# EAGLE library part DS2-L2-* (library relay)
RELAY NAiS bistable, 2 x switch, 4 A/250 V

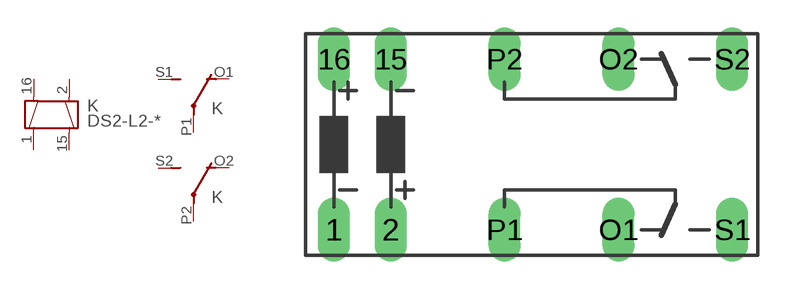
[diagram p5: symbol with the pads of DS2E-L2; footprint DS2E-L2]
Designator prefix K; gates 1=K2 2=U 3=U

## DS2-L2-1.5V (OC_FARNELL: unknown; OC_NEWARK: unknown), DS2-L2-12V (OC_FARNELL: unknown; OC_NEWARK: unknown), DS2-L2-24V (OC_FARNELL: unknown; OC_NEWARK: unknown), DS2-L2-3V (OC_FARNELL: unknown; OC_NEWARK: unknown), DS2-L2-48V (OC_FARNELL: unknown; OC_NEWARK: unknown), DS2-L2-5V (OC_FARNELL: unknown; OC_NEWARK: unknown), DS2-L2-6V (OC_FARNELL: unknown; OC_NEWARK: unknown), DS2-L2-9V (OC_FARNELL: unknown; OC_NEWARK: unknown)  [DS2E-L2]
1  1:2  pas
2  1:3  pas
15  1:4  pas
16  1:1  pas
O1  2:O  pas
O2  3:O  pas
P1  2:P  pas
P2  3:P  pas
S1  2:S  pas
S2  3:S  pas

## Footprint DS2E-L2 (pad centres in mm)
RELAY 2 x switch, 4 A/250 V, NAiS
drill 0.914 long: 1 -7.62,-3.81; 2 -5.08,-3.81; 15 -5.08,3.81; 16 -7.62,3.81; O1 5.08,-3.81; O2 5.08,3.81; P1 0,-3.81; P2 0,3.81; S1 10.16,-3.81; S2 10.16,3.81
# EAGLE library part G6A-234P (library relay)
RELAY 2 x switch, 0.3 A/125 V AC, 1 A/30 V DC, Omron

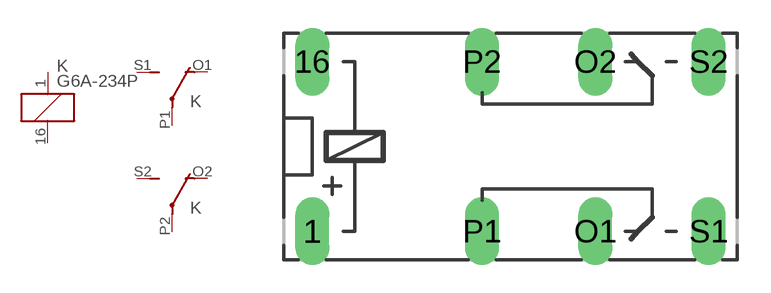
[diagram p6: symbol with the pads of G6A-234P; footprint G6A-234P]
Designator prefix K; gates 1=K 2=U 3=U

## G6A-234P (OC_FARNELL: unknown; OC_NEWARK: unknown)  [G6A-234P]
1  1:1  pas
16  1:2  pas
O1  2:O  pas
O2  3:O  pas
P1  2:P  pas
P2  3:P  pas
S1  2:S  pas
S2  3:S  pas

## Footprint G6A-234P (pad centres in mm)
RELAY 2 x switch, 0.3 A/125 V AC, 1 A/30 V DC, Omron
drill 1.016 long: 1 -3.81,-3.81; 16 -3.81,3.81; O1 8.89,-3.81; O2 8.89,3.81; P1 3.81,-3.81; P2 3.81,3.81; S1 13.97,-3.81; S2 13.97,3.81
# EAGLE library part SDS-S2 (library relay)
RELAY monostable, 2 x norm. open, 2 x norm. closed, 5 A/250 V AC/DC, NAiS

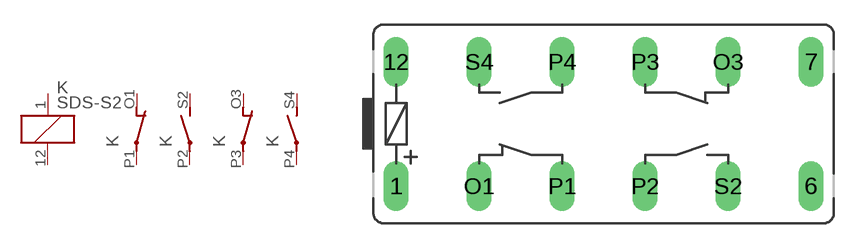
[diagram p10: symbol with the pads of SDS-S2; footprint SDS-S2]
Designator prefix K; gates 1=K 5=S 3=S 2=O 4=O

## SDS-S2 (OC_FARNELL: unknown; OC_NEWARK: unknown)  [SDS-S2]
1  1:1  pas
12  1:2  pas
O1  2:O  pas
O3  4:O  pas
P1  2:P  pas
P2  3:P  pas
P3  4:P  pas
P4  5:P  pas
S2  3:S  pas
S4  5:S  pas

## Footprint SDS-S2 (pad centres in mm)
RELAY mono stable, 2 x norm. open, 2 x norm. closed, 5 A/250 V, AC/DC, NAiS
drill 1.016 long: 1 -12.7,-3.81; 6 12.7,-3.81; 7 12.7,3.81; 12 -12.7,3.81; O1 -7.62,-3.81; O3 7.62,3.81; P1 -2.54,-3.81; P2 2.54,-3.81; P3 2.54,3.81; P4 -2.54,3.81; S2 7.62,-3.81; S4 -7.62,3.81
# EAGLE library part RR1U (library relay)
RELAY reed, polarity, 1 x switch with shield

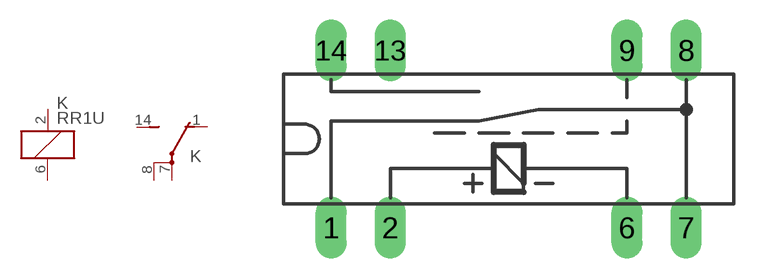
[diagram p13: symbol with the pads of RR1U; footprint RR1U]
Designator prefix K; gates 1=K 2=U1

## RR1U (OC_FARNELL: unknown; OC_NEWARK: unknown)  [RR1U]
1  2:O  pas
2  1:1  pas
6  1:2  pas
7  2:P  pas
8  2:P  pas
14  2:S  pas

## Footprint RR1U (pad centres in mm)
RELAY reed, polarity, 1 x switch with shield
drill 0.813 long: 1 -7.62,-3.81; 2 -5.08,-3.81; 6 5.08,-3.81; 7 7.62,-3.81; 8 7.62,3.81; 9 5.08,3.81; 13 -5.08,3.81; 14 -7.62,3.81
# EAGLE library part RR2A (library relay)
RELAY reed, polarity, 2 x norm. open

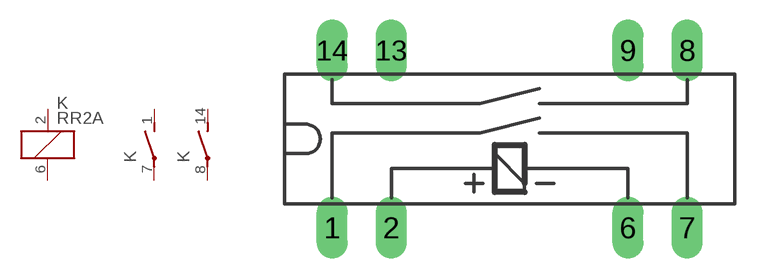
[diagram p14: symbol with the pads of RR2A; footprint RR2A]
Designator prefix K; gates 1=K 2=S 3=S

## RR2A (OC_FARNELL: unknown; OC_NEWARK: unknown)  [RR2A]
1  2:S  pas
2  1:1  pas
6  1:2  pas
7  2:P  pas
8  3:P  pas
14  3:S  pas

## Footprint RR2A (pad centres in mm)
RELAY reed, polarity, 2 x norm. open
drill 0.813 long: 1 -7.62,-3.81; 2 -5.08,-3.81; 6 5.08,-3.81; 7 7.62,-3.81; 8 7.62,3.81; 9 5.08,3.81; 13 -5.08,3.81; 14 -7.62,3.81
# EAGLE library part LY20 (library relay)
RELAY 2 x switch, Omron

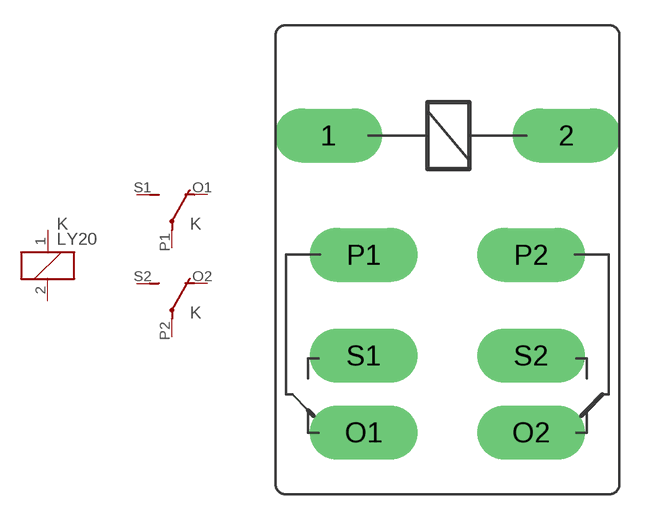
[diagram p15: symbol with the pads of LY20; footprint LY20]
Designator prefix K; gates 1=K 2=U 3=U

## LY20 (OC_FARNELL: unknown; OC_NEWARK: unknown)  [LY20]
1  1:1  pas
2  1:2  pas
O1  2:O  pas
O2  3:O  pas
P1  2:P  pas
P2  3:P  pas
S1  2:S  pas
S2  3:S  pas

## Footprint LY20 (pad centres in mm)
RELAY 2 x switch, Omron
drill 2.21 long: 1 -7.112,0; 2 7.112,0; O1 -5.004,-17.755; O2 5.004,-17.755; P1 -5.004,-7.137; P2 5.004,-7.137; S1 -5.004,-13.157; S2 5.004,-13.157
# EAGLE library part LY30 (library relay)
RELAY 3 x switch, Omron

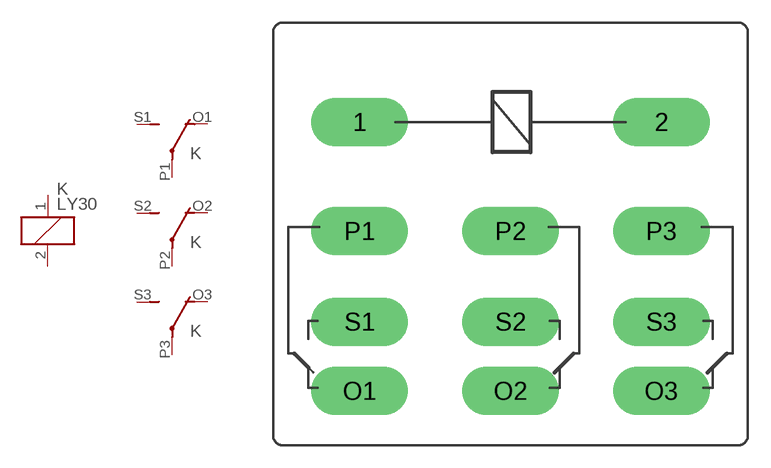
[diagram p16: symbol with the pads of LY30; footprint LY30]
Designator prefix K; gates 1=K 2=U 3=U 4=U

## LY30 (OC_FARNELL: unknown; OC_NEWARK: unknown)  [LY30]
1  1:1  pas
2  1:2  pas
O1  2:O  pas
O2  3:O  pas
O3  4:O  pas
P1  2:P  pas
P2  3:P  pas
P3  4:P  pas
S1  2:S  pas
S2  3:S  pas
S3  4:S  pas

## Footprint LY30 (pad centres in mm)
RELAY 3 x switch, Omron
drill 2.21 long: 1 -10.008,0; 2 10.008,0; O1 -10.008,-17.856; O2 0,-17.856; O3 10.008,-17.856; P1 -10.008,-7.239; P2 0,-7.239; P3 10.008,-7.239; S1 -10.008,-13.259; S2 0,-13.259; S3 10.008,-13.259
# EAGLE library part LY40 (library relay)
RELAY 4 x switch, Omron

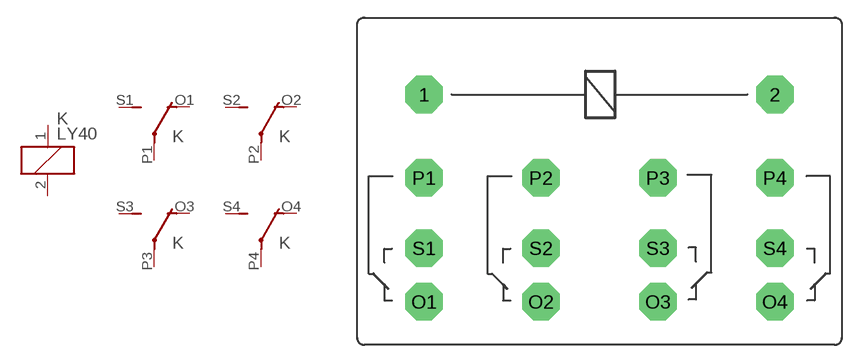
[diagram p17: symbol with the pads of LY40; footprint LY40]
Designator prefix K; gates 1=K 2=U 3=U 4=U 5=U

## LY40 (OC_FARNELL: unknown; OC_NEWARK: unknown)  [LY40]
1  1:1  pas
2  1:2  pas
O1  2:O  pas
O2  3:O  pas
O3  4:O  pas
O4  5:O  pas
P1  2:P  pas
P2  3:P  pas
P3  4:P  pas
P4  5:P  pas
S1  2:S  pas
S2  3:S  pas
S3  4:S  pas
S4  5:S  pas

## Footprint LY40 (pad centres in mm)
RELAY 4 x switch, Omron
drill 2.21 octagon: 1 -15.011,0; 2 15.011,0; O1 -15.011,-17.755; O2 -5.004,-17.755; O3 5.004,-17.755; O4 15.011,-17.755; P1 -15.011,-7.137; P2 -5.004,-7.137; P3 5.004,-7.137; P4 15.011,-7.137; S1 -15.011,-13.157; S2 -5.004,-13.157; S3 5.004,-13.157; S4 15.011,-13.157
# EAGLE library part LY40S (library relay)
RELAY 4 x switch, Omron

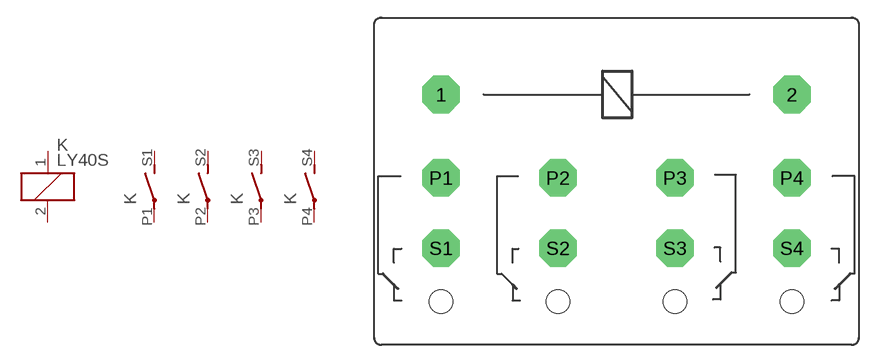
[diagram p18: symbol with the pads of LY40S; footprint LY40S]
Designator prefix K; gates 1=K 2=S 3=S 4=S 5=S

## LY40S (OC_FARNELL: unknown; OC_NEWARK: unknown)  [LY40S]
1  1:1  pas
2  1:2  pas
P1  2:P  pas
P2  3:P  pas
P3  4:P  pas
P4  5:P  pas
S1  2:S  pas
S2  3:S  pas
S3  4:S  pas
S4  5:S  pas

## Footprint LY40S (pad centres in mm)
RELAY 4 x switch, Omron
drill 2.21 octagon: 1 -15.011,0; 2 15.011,0; P1 -15.011,-7.137; P2 -5.004,-7.137; P3 5.004,-7.137; P4 15.011,-7.137; S1 -15.011,-13.157; S2 -5.004,-13.157; S3 5.004,-13.157; S4 15.011,-13.157
hole 2.007 at -15.011,-17.755
hole 2.007 at -5.004,-17.755
hole 2.007 at 5.004,-17.755
hole 2.007 at 15.011,-17.755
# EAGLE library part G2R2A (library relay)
RELAY 2 x norm. open, Omron

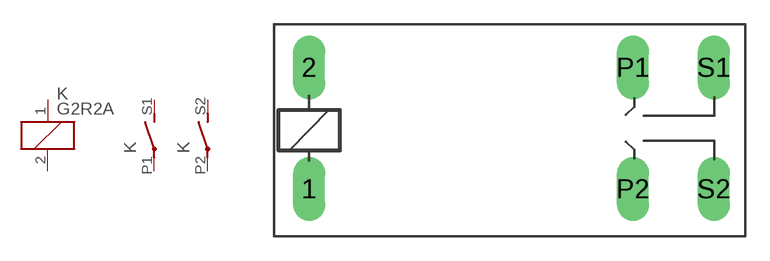
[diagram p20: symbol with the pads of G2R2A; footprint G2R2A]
Designator prefix K; gates 1=K 2=S 3=S

## G2R2A (MPN: G2R-2A-DC24; OC_FARNELL: 6985269; OC_NEWARK: 36M5257)  [G2R2A]
1  1:1  pas
2  1:2  pas
P1  2:P  pas
P2  3:P  pas
S1  2:S  pas
S2  3:S  pas

## Footprint G2R2A (pad centres in mm)
RELAY 2 x norm. open, Omron
drill 1.321 long: 1 -2.54,-3.683; 2 -2.54,3.81; P1 17.45,3.81; P2 17.45,-3.683; S1 22.454,3.81; S2 22.454,-3.683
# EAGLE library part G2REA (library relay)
RELAY 1 x norm. open, high current, Omron

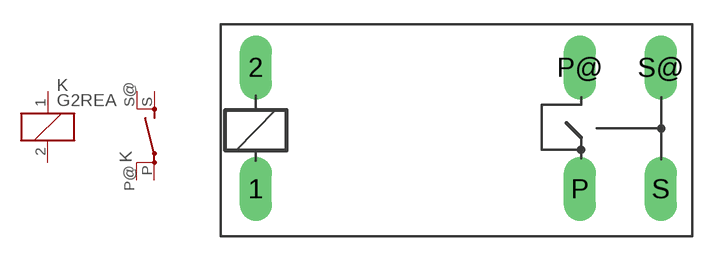
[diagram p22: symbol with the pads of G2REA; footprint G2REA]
Designator prefix K; gates 1=K 2=SD

## G2REA (OC_FARNELL: unknown; OC_NEWARK: unknown)  [G2REA]
1  1:1  pas
2  1:2  pas
P  2:P  pas
P@  2:P  pas
S  2:S  pas
S@  2:S  pas

## Footprint G2REA (pad centres in mm)
RELAY 1 x norm. open, high current, Omron
drill 1.321 long: 1 -2.54,-3.683; 2 -2.54,3.81; P 17.45,-3.683; P@ 17.45,3.81; S 22.454,-3.683; S@ 22.454,3.81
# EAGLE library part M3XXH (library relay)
RELAY 1 x switch

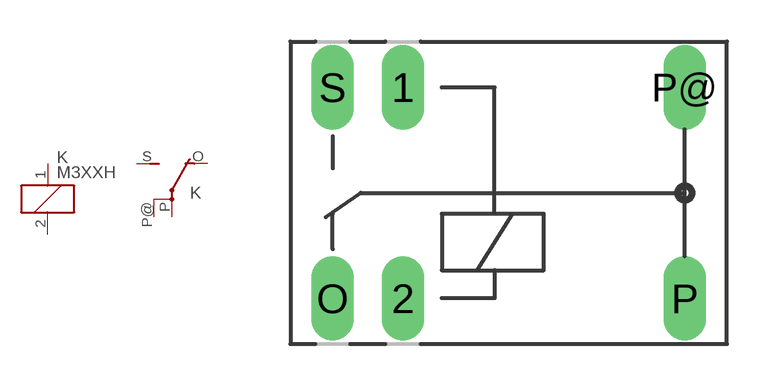
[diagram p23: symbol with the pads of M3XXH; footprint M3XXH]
Designator prefix K; gates 1=K 2=U1

## M3XXH (OC_FARNELL: unknown; OC_NEWARK: unknown)  [M3XXH]
1  1:1  pas
2  1:2  pas
O  2:O  pas
P  2:P  pas
P@  2:P  pas
S  2:S  pas

## Footprint M3XXH (pad centres in mm)
RELAY 1 x switch
drill 1.016 long: 1 -3.81,3.81; 2 -3.81,-3.81; O -6.35,-3.81; P 6.35,-3.81; P@ 6.35,3.81; S -6.35,3.81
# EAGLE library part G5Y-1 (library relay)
RELAY RF Relay up to 900 MHz, 1 x switch, 10 W, Omron

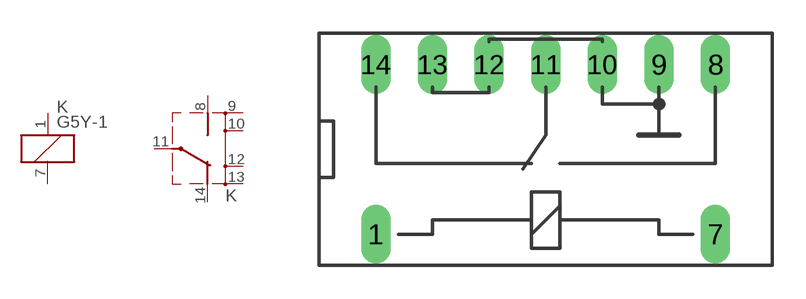
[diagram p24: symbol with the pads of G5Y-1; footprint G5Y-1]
Designator prefix K; gates 1=K 2=U_M4

## G5Y-1 (OC_FARNELL: unknown; OC_NEWARK: unknown)  [G5Y-1]
1  1:1  pas
7  1:2  pas
8  2:S  pas
9  2:ES  pas
10  2:ES  pas
11  2:P  pas
12  2:ES  pas
13  2:ES  pas
14  2:O  pas

## Footprint G5Y-1 (pad centres in mm)
RELAY RF up to 900 MHz, 1 x switch, 10 W, Omron
drill 0.813 long: 1 -7.62,-3.81; 7 7.62,-3.81; 8 7.62,3.81; 9 5.08,3.81; 10 2.54,3.81; 11 0,3.81; 12 -2.54,3.81; 13 -5.08,3.81; 14 -7.62,3.81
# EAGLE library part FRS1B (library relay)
RELAY 1 x switch, same as V23101-D6-A201, Siemens

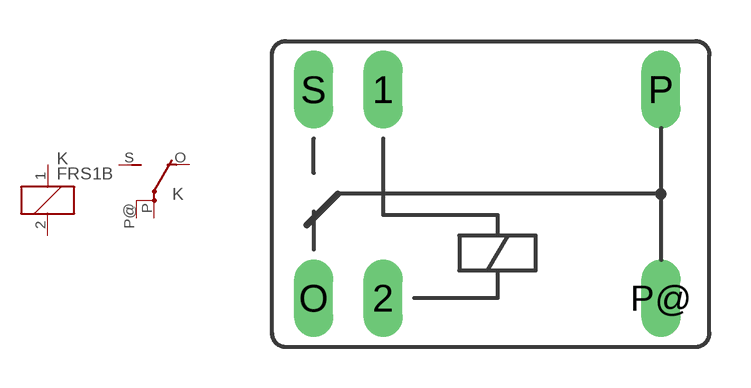
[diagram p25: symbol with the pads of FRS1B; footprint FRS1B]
Designator prefix K; gates 1=K 2=U1

## FRS1B (OC_FARNELL: unknown; OC_NEWARK: unknown)  [FRS1B]
1  1:1  pas
2  1:2  pas
O  2:O  pas
P  2:P  pas
P@  2:P  pas
S  2:S  pas

## Footprint FRS1B (pad centres in mm)
RELAY 1 x switch, same as V23101-D6-A201, Siemens
drill 0.914 long: 1 0,3.81; 2 0,-3.81; O -2.54,-3.81; P 10.16,3.81; P@ 10.16,-3.81; S -2.54,3.81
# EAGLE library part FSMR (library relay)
RELAY 1 x switch, same as FBR21D/H, Fujitsu

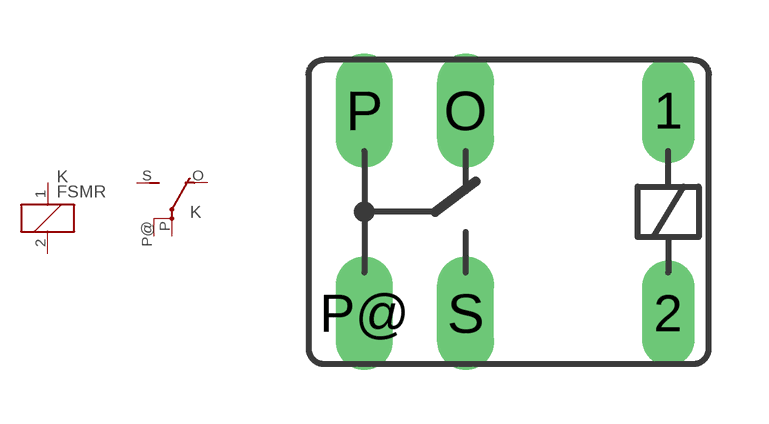
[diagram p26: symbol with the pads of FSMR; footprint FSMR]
Designator prefix K; gates 1=K 2=U1

## FSMR (OC_FARNELL: unknown; OC_NEWARK: unknown)  [FSMR]
1  1:1  pas
2  1:2  pas
O  2:O  pas
P  2:P  pas
P@  2:P  pas
S  2:S  pas

## Footprint FSMR (pad centres in mm)
RELAY 1 x switch, same as FBR21D/H, Fujitsu
drill 0.813 long: 1 5.08,2.54; 2 5.08,-2.54
drill 0.914 long: O 0,2.54; P -2.54,2.54; P@ -2.54,-2.54; S 0,-2.54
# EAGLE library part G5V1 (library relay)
RELAY 1 x switch, 0.5 A/125 V AC, 1 A/24 V DC , Omron

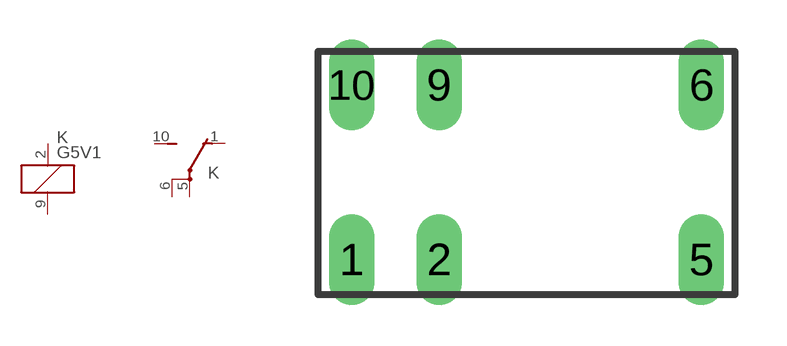
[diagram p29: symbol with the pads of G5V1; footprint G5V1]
Designator prefix K; gates 1=K 2=U1

## G5V1 (MPN: G5V-1-DC24; OC_FARNELL: 9949593; OC_NEWARK: 36M6377)  [G5V1]
1  2:O  pas
2  1:1  pas
5  2:P  pas
6  2:P  pas
9  1:2  pas
10  2:S  pas

## Footprint G5V1 (pad centres in mm)
RELAY 1 x switch, 0.5 A/125 V AC, 1 A/24 V DC , Omron
drill 0.813 long: 1 -5.08,-2.54; 2 -2.54,-2.54; 5 5.08,-2.54; 6 5.08,2.54; 9 -2.54,2.54; 10 -5.08,2.54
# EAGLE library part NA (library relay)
RELAY

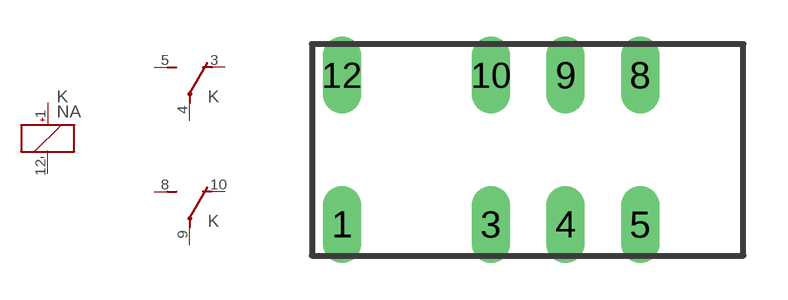
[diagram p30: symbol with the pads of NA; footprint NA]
Designator prefix K; gates 1=K+- 2=U 3=U

## NA (OC_FARNELL: unknown; OC_NEWARK: unknown)  [NA]
1  1:+  pas
3  2:O  pas
4  2:P  pas
5  2:S  pas
8  3:S  pas
9  3:P  pas
10  3:O  pas
12  1:-  pas

## Footprint NA (pad centres in mm)
RELAY dummy
drill 0.8 long: 1 -6.35,-2.54; 3 -1.27,-2.54; 4 1.27,-2.54; 5 3.81,-2.54; 8 3.81,2.54; 9 1.27,2.54; 10 -1.27,2.54; 12 -6.35,2.54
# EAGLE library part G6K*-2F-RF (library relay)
OMRON High Frequency Relay G6K-RF Compact High Frequency Relays with 2 Form C (DPDT) Contacts Handles 1 A, 30 VDC discrete load and 1 W at 1 GHz high frequency load D20G6KRF0602.pdf

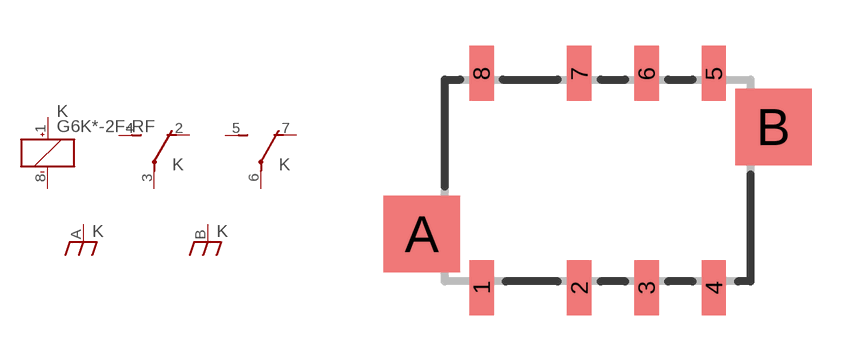
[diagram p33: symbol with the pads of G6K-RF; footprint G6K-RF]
Designator prefix K; gates 1=K+- A=U B=U S1=SHIELD S2=SHIELD

## G6K-2F-RF (MF: OMRON COMPONENTS USA; MPN: G6K-2F-RF-DC12; OC_FARNELL: 1448181; OC_NEWARK: 73C8948), G6KU-2F-RF (OC_FARNELL: unknown; OC_NEWARK: unknown)  [G6K-RF]
1  1:+  pas
2  A:O  pas
3  A:P  pas
4  A:S  pas
5  B:S  pas
6  B:P  pas
7  B:O  pas
8  1:-  pas
A  S1:SH  pas
B  S2:SH  pas

## Footprint G6K-RF (pad centres in mm)
OMRON High Frequency Relay G6K-RF D20G6KRF0602.pdf
smd 0.8 x 1.8: 1 -3.8,-3.5; 2 -0.6,-3.5; 3 1.6,-3.5; 4 3.8,-3.5; 5 3.8,3.5; 6 1.6,3.5; 7 -0.6,3.5; 8 -3.8,3.5
smd 2.5 x 2.5: A -5.75,-1.75; B 5.75,1.75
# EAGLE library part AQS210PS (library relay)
PhotoMOS Relay NAiS Source: http://www.mew-europe.com/.. pti_en.pdf

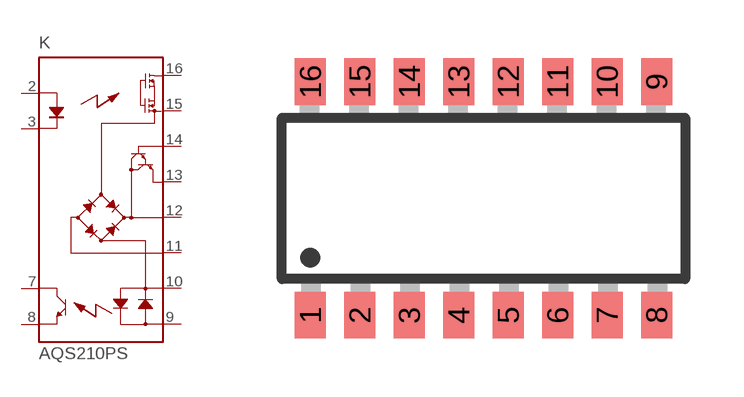
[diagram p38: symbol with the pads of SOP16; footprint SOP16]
Designator prefix K

## AQS210PS (OC_FARNELL: unknown; OC_NEWARK: unknown)  [SOP16]
2  2  pas
3  3  pas
7  7  pas
8  8  pas
9  9  pas
10  10  pas
11  11  pas
12  12  pas
13  13  pas
14  14  pas
15  15  pas
16  16  pas

## Footprint SOP16 (pad centres in mm)
SOP 16 - AQS21, AQS22, AQS610TS Series NAiS Source: http://www.mew-europe.com/.. pti_en.pdf
smd 0.8 x 1.2: 1 -4.445,-3; 2 -3.175,-3; 3 -1.905,-3; 4 -0.635,-3; 5 0.635,-3; 6 1.905,-3; 7 3.175,-3; 8 4.445,-3; 9 4.445,3; 10 3.175,3; 11 1.905,3; 12 0.635,3; 13 -0.635,3; 14 -1.905,3; 15 -3.175,3; 16 -4.445,3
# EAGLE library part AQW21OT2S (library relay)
PhotoMOS Relay NAiS Source: http://www.mew-europe.com/.. pti_en.pdf

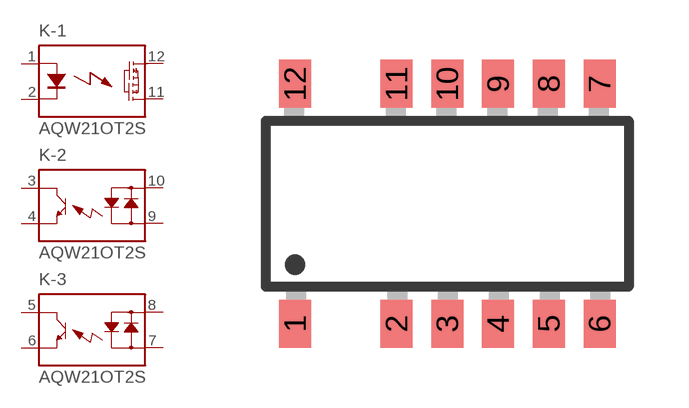
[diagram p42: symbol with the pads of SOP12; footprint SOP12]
Designator prefix K; gates -1=PHOTOMOS_2D -2=PHOTO-DETECTOR -3=PHOTO-DETECTOR

## AQW21OT2S (OC_FARNELL: unknown; OC_NEWARK: unknown)  [SOP12]
1  -1:A  pas
2  -1:K  pas
3  -2:K  pas
4  -2:E  pas
5  -3:K  pas
6  -3:E  pas
7  -3:AC2  pas
8  -3:AC1  pas
9  -2:AC2  pas
10  -2:AC1  pas
11  -1:DS2  pas
12  -1:DS1  pas

## Footprint SOP12 (pad centres in mm)
AOP 12- AQW21.T2s Series NAiS Source: http://www.mew-europe.com/.. pti_en.pdf
smd 0.8 x 1.2: 1 -3.81,-3; 2 -1.27,-3; 3 0,-3; 4 1.27,-3; 5 2.54,-3; 6 3.81,-3; 7 3.81,3; 8 2.54,3; 9 1.27,3; 10 0,3; 11 -1.27,3; 12 -3.81,3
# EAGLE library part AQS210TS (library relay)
PhotoMOS Relay NAiS Source: http://www.mew-europe.com/.. pti_en.pdf

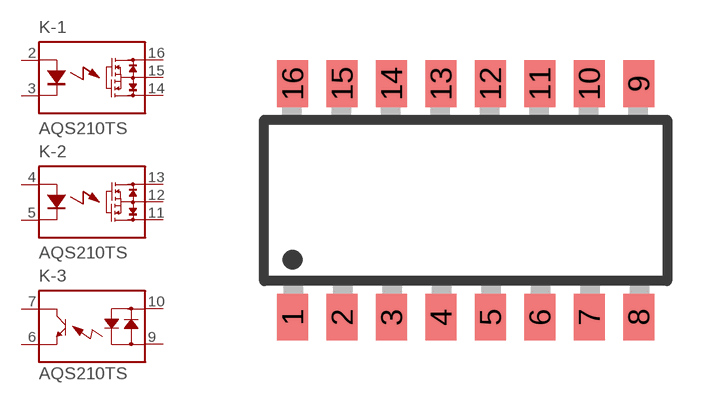
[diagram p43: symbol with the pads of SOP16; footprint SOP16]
Designator prefix K; gates -1=PHOTO-REKAY2D1S -2=PHOTO-REKAY2D1S -3=PHOTO-DETECTOR

## AQS210TS (OC_FARNELL: unknown; OC_NEWARK: unknown)  [SOP16]
2  -1:A  pas
3  -1:K  pas
4  -2:A  pas
5  -2:K  pas
6  -3:E  pas
7  -3:K  pas
9  -3:AC2  pas
10  -3:AC1  pas
11  -2:D2  pas
12  -2:S  pas
13  -2:D1  pas
14  -1:D2  pas
15  -1:S  pas
16  -1:D1  pas

## Footprint SOP16 (pad centres in mm)
SOP 16 - AQS21, AQS22, AQS610TS Series NAiS Source: http://www.mew-europe.com/.. pti_en.pdf
smd 0.8 x 1.2: 1 -4.445,-3; 2 -3.175,-3; 3 -1.905,-3; 4 -0.635,-3; 5 0.635,-3; 6 1.905,-3; 7 3.175,-3; 8 4.445,-3; 9 4.445,3; 10 3.175,3; 11 1.905,3; 12 0.635,3; 13 -0.635,3; 14 -1.905,3; 15 -3.175,3; 16 -4.445,3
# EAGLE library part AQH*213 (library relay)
SOLID STATE RELAY NAiS Source: http://www.mew-europe.com/.. en_ds_61613_0000.pdf

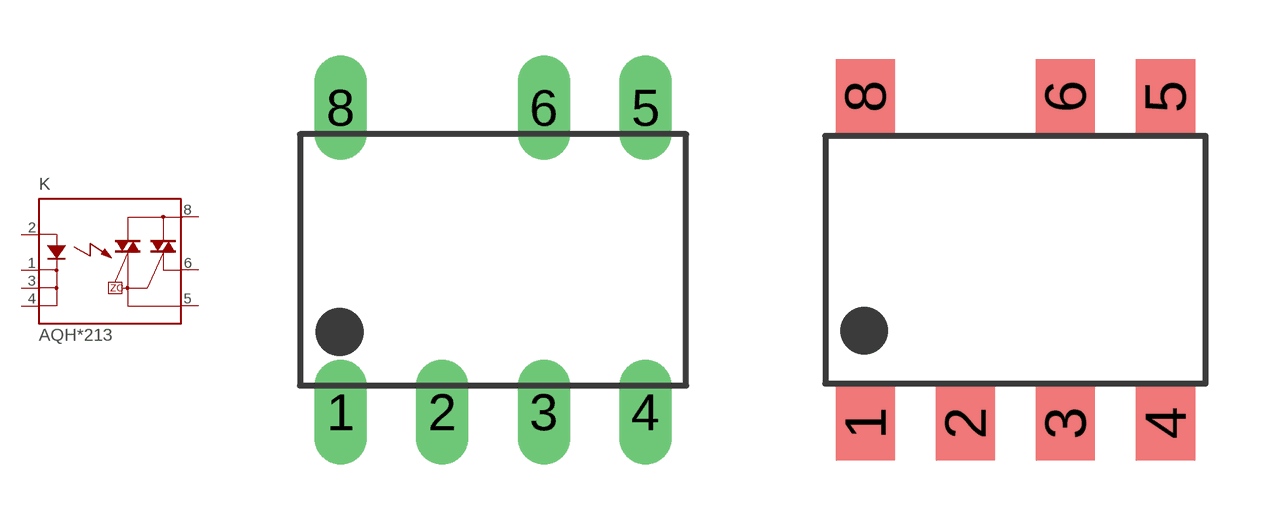
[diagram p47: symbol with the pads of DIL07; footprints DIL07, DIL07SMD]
Designator prefix K

## AQH213 (OC_FARNELL: unknown; OC_NEWARK: unknown)  [DIL07]
1  K  pas
2  A  pas
3  K1  pas
4  K2  pas
5  DS2  pas
6  DS3  pas
8  DS1  pas

## AQH213A (OC_FARNELL: unknown; OC_NEWARK: unknown)  [DIL07SMD]
Pads as for DIL07

## Footprint DIL07 (pad centres in mm)
DIL07 NAiS Source: http://www.mew-europe.com/.. en_ds_61613_0000.pdf
drill 0.8 long: 1 -3.81,-3.81; 2 -1.27,-3.81; 3 1.27,-3.81; 4 3.81,-3.81; 5 3.81,3.81; 6 1.27,3.81; 8 -3.81,3.81

## Footprint DIL07SMD (pad centres in mm)
DIL07 NAiS Source: http://www.mew-europe.com/.. en_ds_61613_0000.pdf
smd 1.5 x 1.9: 1 -3.81,-4.15; 2 -1.27,-4.15; 3 1.27,-4.15; 4 3.81,-4.15; 5 3.81,4.15; 6 1.27,4.15; 8 -3.81,4.15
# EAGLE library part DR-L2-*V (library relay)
HIGHLY RELIABLE MINIATURE DIP RELAYS 2 Coil Latching NAiS Source: www.mew-europe.com/ac/download/datasheet/relay/dr_en.pdf

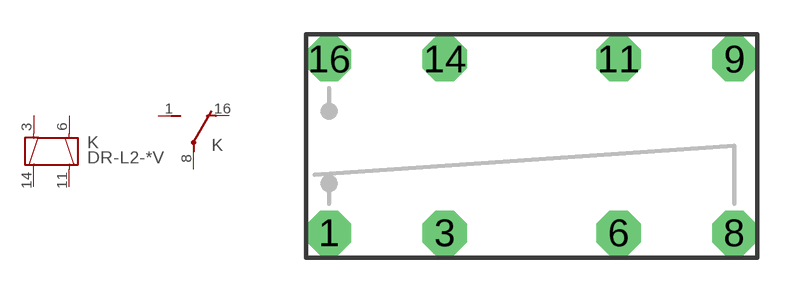
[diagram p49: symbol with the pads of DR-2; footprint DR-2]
Designator prefix K; gates C=U A=K2

## DR-L2-12V (OC_FARNELL: unknown; OC_NEWARK: unknown), DR-L2-24V (OC_FARNELL: unknown; OC_NEWARK: unknown), DR-L2-5V (OC_FARNELL: unknown; OC_NEWARK: unknown)  [DR-2]
1  C:S  pas
3  A:1  pas
6  A:3  pas
8  C:P  pas
11  A:4  pas
14  A:2  pas
16  C:O  pas

## Footprint DR-2 (pad centres in mm)
DR Relay NAiS Source: www.mew-europe.com/ac/download/ datasheet/relay/dr_en.pdf
drill 1.3 octagon: 1 -8.89,-3.81; 3 -3.81,-3.81; 6 3.81,-3.81; 8 8.89,-3.81; 9 8.89,3.81; 11 3.81,3.81; 14 -3.81,3.81; 16 -8.89,3.81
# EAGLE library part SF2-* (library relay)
POLARISED, MONOSTABLE RELAY WITH FORCIBLY GUIDED CONTACTS NAiS Source: http://www.mew-europe.com/.. en_ds_61404_0001.pdf

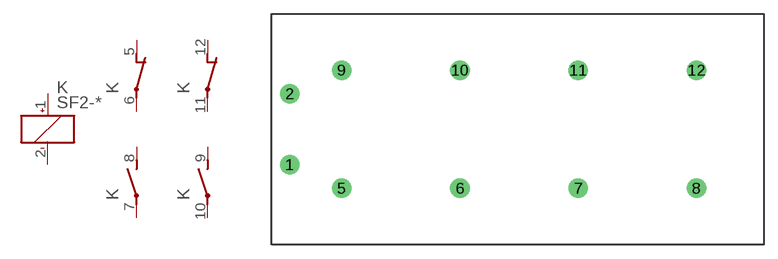
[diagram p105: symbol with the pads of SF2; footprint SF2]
Designator prefix K; gates S=K+- 1=O 2=O 3=S 4=S

## SF2-12V (MF: FARNELL; MPN: SF2-12V; OC_FARNELL: 625875; OC_NEWARK: 68C0655), SF2-18V (OC_FARNELL: unknown; OC_NEWARK: unknown), SF2-21V (OC_FARNELL: unknown; OC_NEWARK: unknown), SF2-24V (MPN: SF2-24V; OC_FARNELL: 1124064; OC_NEWARK: 31M0404), SF2-36V (OC_FARNELL: unknown; OC_NEWARK: unknown), SF2-48V (OC_FARNELL: unknown; OC_NEWARK: unknown), SF2-5V (OC_FARNELL: unknown; OC_NEWARK: unknown), SF2-60V (OC_FARNELL: unknown; OC_NEWARK: unknown), SF2-9V (OC_FARNELL: unknown; OC_NEWARK: unknown)  [SF2]
1  S:+  pas
2  S:-  pas
5  1:O  pas
6  1:P  pas
7  3:P  pas
8  3:S  pas
9  4:S  pas
10  4:P  pas
11  2:P  pas
12  2:O  pas

## Footprint SF2 (pad centres in mm)
POLARISED, MONOSTABLE RELAY WITH FORCIBLY GUIDED CONTACTS NAiS Source: http://www.mew-europe.com/.. en_ds_61404_0001.pdf Data sheet
drill 1.4: 1 -24.638,-3.81; 2 -24.638,3.81; 5 -19.05,-6.35; 6 -6.35,-6.35; 7 6.35,-6.35; 8 19.05,-6.35; 9 -19.05,6.35; 10 -6.35,6.35; 11 6.35,6.35; 12 19.05,6.35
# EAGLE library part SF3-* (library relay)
POLARISED, MONOSTABLE RELAY WITH FORCIBLY GUIDED CONTACTS NAiS Source: http://www.mew-europe.com/.. en_ds_61404_0001.pdf

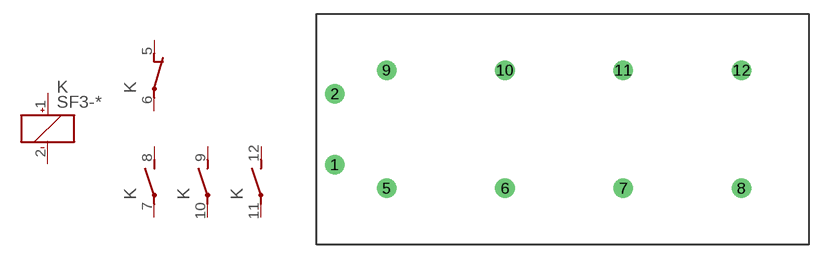
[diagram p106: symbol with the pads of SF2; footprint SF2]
Designator prefix K; gates 1=K+- 2=O 3=S 4=S 5=S

## SF3-12V (OC_FARNELL: unknown; OC_NEWARK: unknown), SF3-18V (OC_FARNELL: unknown; OC_NEWARK: unknown), SF3-21V (OC_FARNELL: unknown; OC_NEWARK: unknown), SF3-24V (OC_FARNELL: unknown; OC_NEWARK: unknown), SF3-36V (OC_FARNELL: unknown; OC_NEWARK: unknown), SF3-48V (OC_FARNELL: unknown; OC_NEWARK: unknown), SF3-5V (OC_FARNELL: unknown; OC_NEWARK: unknown), SF3-60V (OC_FARNELL: unknown; OC_NEWARK: unknown), SF3-9V (OC_FARNELL: unknown; OC_NEWARK: unknown)  [SF2]
1  1:+  pas
2  1:-  pas
5  2:O  pas
6  2:P  pas
7  3:P  pas
8  3:S  pas
9  4:S  pas
10  4:P  pas
11  5:P  pas
12  5:S  pas

## Footprint SF2 (pad centres in mm)
POLARISED, MONOSTABLE RELAY WITH FORCIBLY GUIDED CONTACTS NAiS Source: http://www.mew-europe.com/.. en_ds_61404_0001.pdf Data sheet
drill 1.4: 1 -24.638,-3.81; 2 -24.638,3.81; 5 -19.05,-6.35; 6 -6.35,-6.35; 7 6.35,-6.35; 8 19.05,-6.35; 9 -19.05,6.35; 10 -6.35,6.35; 11 6.35,6.35; 12 19.05,6.35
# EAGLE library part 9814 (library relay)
Surface Mount Reed Relays Source: COTO TECHNOLOGY - 9852-03-00 - RELAY - 91349.pdf

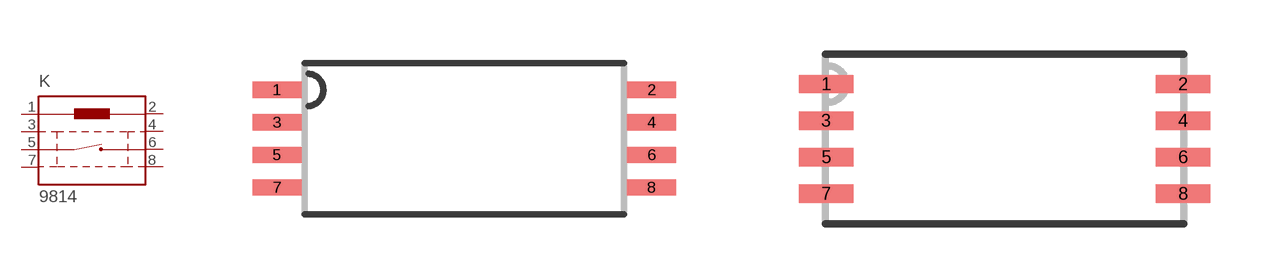
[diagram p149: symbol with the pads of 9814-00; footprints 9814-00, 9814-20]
Designator prefix K

## 9814-03-00 (MF: COTO TECHNOLOGY; MPN: 9814-03-00; OC_FARNELL: unknown; OC_NEWARK: 29H2537), 9814-05-00 (MF: COTO TECHNOLOGY; MPN: 9814-05-00; OC_FARNELL: 1081691; OC_NEWARK: 29H2538)  [9814-00]
1  1  pas
2  2  pas
3  3  pas
4  4  pas
5  5  pas
6  6  pas
7  7  pas
8  8  pas

## 9814-03-20 (MF: COTO TECHNOLOGY; MPN: 9814-03-20; OC_FARNELL: unknown; OC_NEWARK: 83H2026), 9814-05-20 (MF: COTO TECHNOLOGY; MPN: 9814-05-20; OC_FARNELL: unknown; OC_NEWARK: 83H2028)  [9814-20]
Pads as for 9814-00

## Footprint 9814-00 (pad centres in mm)
Surface Mount Reed Relays Gull Wing Source: COTO TECHNOLOGY - 9852-03-00 - RELAY - 91349.pdf
smd 1.524 x 0.508: 1 -5.842,1.524; 2 5.842,1.524; 3 -5.842,0.508; 4 5.842,0.508; 5 -5.842,-0.508; 6 5.842,-0.508; 7 -5.842,-1.524; 8 5.842,-1.524

## Footprint 9814-20 (pad centres in mm)
Surface Mount Reed Relays J-Lead Source: COTO TECHNOLOGY - 9852-03-00 - RELAY - 91349.pdf
smd 1.524 x 0.508: 1 -4.953,1.524; 2 4.953,1.524; 3 -4.953,0.508; 4 4.953,0.508; 5 -4.953,-0.508; 6 4.953,-0.508; 7 -4.953,-1.524; 8 4.953,-1.524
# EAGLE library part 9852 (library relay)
Surface Mount Reed Relays Source: COTO TECHNOLOGY - 9852-03-00 - RELAY - 91349.pdf

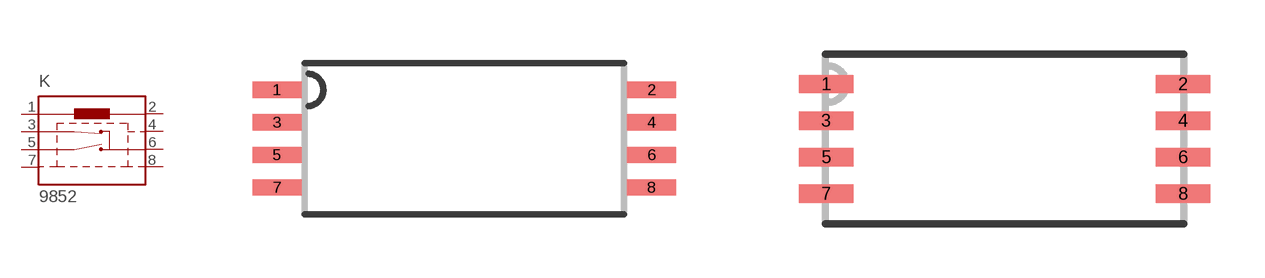
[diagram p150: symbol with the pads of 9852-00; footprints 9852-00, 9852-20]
Designator prefix K

## 9852-03-00 (MF: COTO TECHNOLOGY; MPN: 9852-03-00; OC_FARNELL: 1081692; OC_NEWARK: 29H2540), 9852-05-00 (MF: COTO TECHNOLOGY; MPN: 9852-05-00; OC_FARNELL: 1081693; OC_NEWARK: 84C8955)  [9852-00]
1  1  pas
2  2  pas
3  3  pas
4  4  pas
5  5  pas
6  6  pas
7  7  pas
8  8  pas

## 9852-03-20 (MF: COTO TECHNOLOGY; MPN: 9852-03-20; OC_FARNELL: unknown; OC_NEWARK: 83H2030), 9852-05-20 (MPN: 9852-05-20; OC_FARNELL: 1081642; OC_NEWARK: 46M4523)  [9852-20]
Pads as for 9852-00

## Footprint 9852-00 (pad centres in mm)
Surface Mount Reed Relays Gull Wing Source: COTO TECHNOLOGY - 9852-03-00 - RELAY - 91349.pdf
smd 1.524 x 0.508: 1 -5.842,1.524; 2 5.842,1.524; 3 -5.842,0.508; 4 5.842,0.508; 5 -5.842,-0.508; 6 5.842,-0.508; 7 -5.842,-1.524; 8 5.842,-1.524

## Footprint 9852-20 (pad centres in mm)
Surface Mount Reed Relays J-Lead Source: COTO TECHNOLOGY - 9852-03-00 - RELAY - 91349.pdf
smd 1.524 x 0.508: 1 -4.953,1.524; 2 4.953,1.524; 3 -4.953,0.508; 4 4.953,0.508; 5 -4.953,-0.508; 6 4.953,-0.508; 7 -4.953,-1.524; 8 4.953,-1.524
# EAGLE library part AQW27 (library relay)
PhotoMOSS RELAYS PD Type 2- channel (Form a) Type Source: http://www.ic-on-line.cn/IOL/datasheet/aqw277az_1212830.pdf

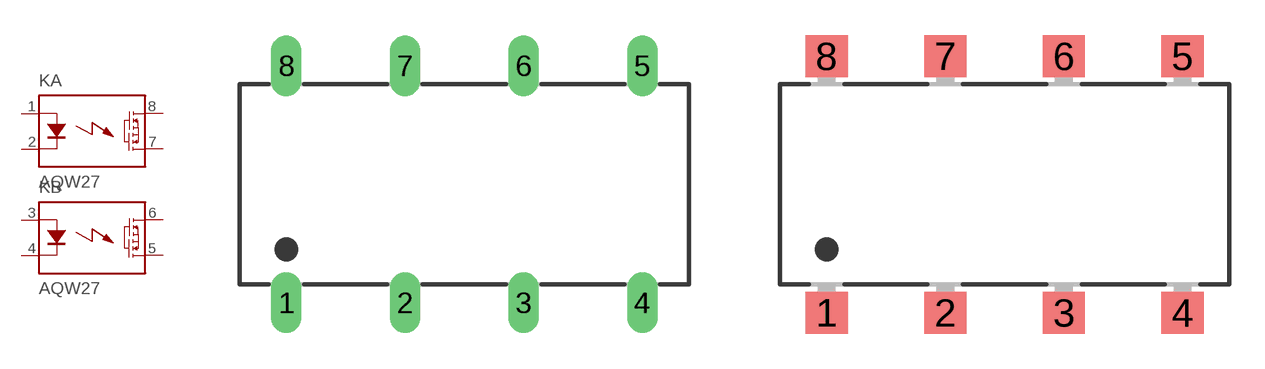
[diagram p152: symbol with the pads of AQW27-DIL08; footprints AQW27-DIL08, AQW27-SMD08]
Designator prefix K; gates A=PHOTO-RELAY-2S B=PHOTO-RELAY-2S

## AQW27  [AQW27-DIL08]
1  A:A  pas
2  A:K  pas
3  B:A  pas
4  B:K  pas
5  B:D2  pas
6  B:D1  pas
7  A:D2  pas
8  A:D1  pas

## AQW27A  [AQW27-SMD08]
Pads as for AQW27-DIL08

## Footprint AQW27-DIL08 (pad centres in mm)
DIL 08 NAiS Source: http://www.mew-europe.com/.. pti_en.pdf
drill 0.8 long: 1 -7.62,-5.08; 2 -2.54,-5.08; 3 2.54,-5.08; 4 7.62,-5.08; 5 7.62,5.08; 6 2.54,5.08; 7 -2.54,5.08; 8 -7.62,5.08

## Footprint AQW27-SMD08 (pad centres in mm)
SMD 08 NAiS Source: http://www.mew-europe.com/.. pti_en.pdf
smd 1.8 x 1.8: 1 -7.62,-5.5; 2 -2.54,-5.5; 3 2.54,-5.5; 4 7.62,-5.5; 5 7.62,5.5; 6 2.54,5.5; 7 -2.54,5.5; 8 -7.62,5.5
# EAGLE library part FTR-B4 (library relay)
ULTRA MINIATURE RELAY 2 POLES - 2 A (Slim Profile Signal Relay) FUJITSU FTR-B4 SERIES Source: FTR-B4.pdf

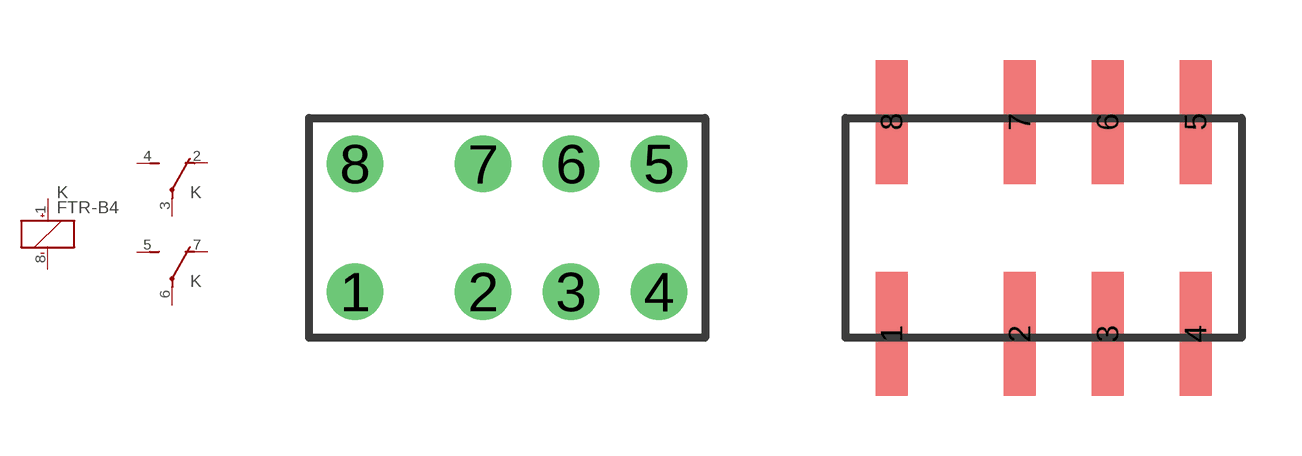
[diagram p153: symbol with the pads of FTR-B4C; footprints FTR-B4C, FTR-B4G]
Designator prefix K; gates K=K+- -1=U -2=U

## FTR-B4C  [FTR-B4C]
1  K:+  pas
2  -1:O  pas
3  -1:P  pas
4  -1:S  pas
5  -2:S  pas
6  -2:P  pas
7  -2:O  pas
8  K:-  pas

## FTR-B4G  [FTR-B4G]
Pads as for FTR-B4C

## FTR-B4S  [FTR-B4S]
Pads as for FTR-B4C

## Footprint FTR-B4C (pad centres in mm)
ULTRA MINIATURE RELAY 2 POLES - 2 A (Slim Profile Signal Relay) FUJITSU FTR-B4 SERIES Source: FTR-B4.pdf
drill 0.9 pad 1.422: 1 -3.8,-1.6; 2 -0.6,-1.6; 3 1.6,-1.6; 4 3.8,-1.6; 5 3.8,1.6; 6 1.6,1.6; 7 -0.6,1.6; 8 -3.8,1.6

## Footprint FTR-B4G (pad centres in mm)
ULTRA MINIATURE RELAY 2 POLES - 2 A (Slim Profile Signal Relay) FUJITSU FTR-B4 SERIES Source: FTR-B4.pdf
smd 0.8 x 3.1: 1 -3.8,-2.65; 2 -0.6,-2.65; 3 1.6,-2.65; 4 3.8,-2.65; 5 3.8,2.65; 6 1.6,2.65; 7 -0.6,2.65; 8 -3.8,2.65

## Footprint FTR-B4S (pad centres in mm)
ULTRA MINIATURE RELAY 2 POLES - 2 A (Slim Profile Signal Relay) FUJITSU FTR-B4 SERIES Source: FTR-B4.pdf
smd 0.8 x 2.25: 1 -3.8,-3.345; 2 -0.6,-3.345; 3 1.6,-3.345; 4 3.8,-3.345; 5 3.8,3.345; 6 1.6,3.345; 7 -0.6,3.345; 8 -3.8,3.345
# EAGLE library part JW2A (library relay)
Power relay Source: Panasonic Electric Works Co., Ltd. / jw.catalog.pdf

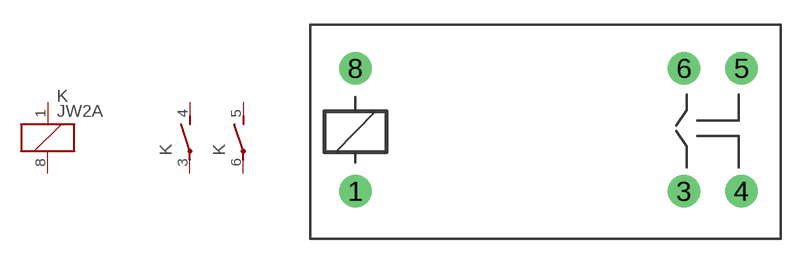
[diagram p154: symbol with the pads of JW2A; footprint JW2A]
Designator prefix K; gates _=K 1=S 2=S

## JW2A  [JW2A]
1  _:1  pas
3  1:P  pas
4  1:S  pas
5  2:S  pas
6  2:P  pas
8  _:2  pas

## Footprint JW2A (pad centres in mm)
Power relay Source: Panasonic Electric Works Co., Ltd. / jw.catalog.pdf
drill 1.321 pad 1.9: 1 -10,-3.683; 3 10,-3.69; 4 13.5,-3.683; 5 13.5,3.817; 6 10,3.81; 8 -10,3.81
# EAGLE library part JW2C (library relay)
Power relay Source: Panasonic Electric Works Co., Ltd. / jw.catalog.pdf

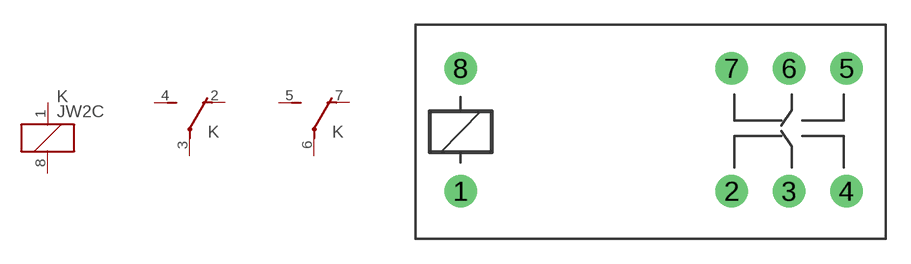
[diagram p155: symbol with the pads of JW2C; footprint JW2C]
Designator prefix K; gates -=K 1=U 2=U

## JW2C  [JW2C]
1  -:1  pas
2  1:O  pas
3  1:P  pas
4  1:S  pas
5  2:S  pas
6  2:P  pas
7  2:O  pas
8  -:2  pas

## Footprint JW2C (pad centres in mm)
Power relay Source: Panasonic Electric Works Co., Ltd. / jw.catalog.pdf
drill 1.321 pad 1.9: 1 -10,-3.683; 2 6.5,-3.683; 3 10,-3.69; 4 13.5,-3.683; 5 13.5,3.817; 6 10,3.81; 7 6.5,3.817; 8 -10,3.81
